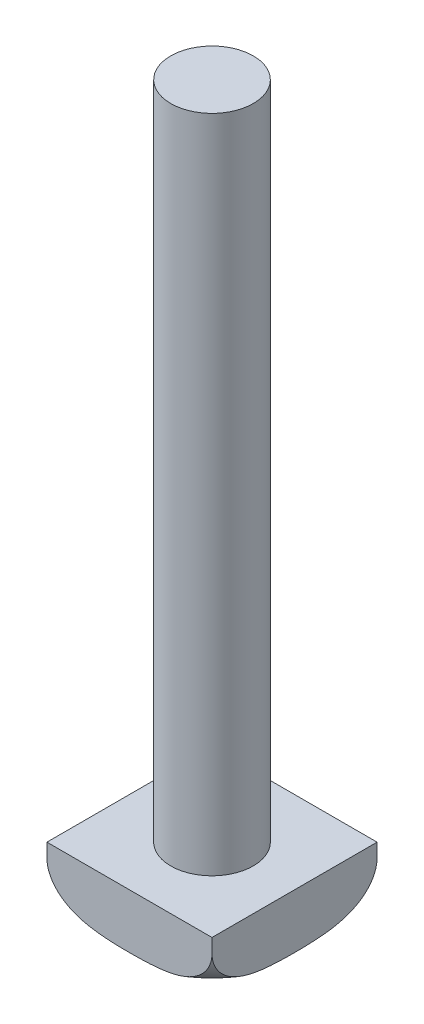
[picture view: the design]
ISO-10303-21;
HEADER;
FILE_DESCRIPTION(('STEP AP214'),'2;1');
FILE_NAME('part.step','',(''),(''),'','','');
FILE_SCHEMA(('AUTOMOTIVE_DESIGN { 1 0 10303 214 1 1 1 1 }'));
ENDSEC;
DATA;
#1=APPLICATION_CONTEXT('core data for automotive mechanical design processes');
#2=APPLICATION_PROTOCOL_DEFINITION('international standard','automotive_design',2000,#1);
#3=PRODUCT_CONTEXT('',#1,'mechanical');
#4=PRODUCT('Part','Part','',(#3));
#5=PRODUCT_RELATED_PRODUCT_CATEGORY('part','',(#4));
#6=PRODUCT_DEFINITION_FORMATION('','',#4);
#7=PRODUCT_DEFINITION_CONTEXT('part definition',#1,'design');
#8=PRODUCT_DEFINITION('design','',#6,#7);
#9=PRODUCT_DEFINITION_SHAPE('','',#8);
#10=(LENGTH_UNIT() NAMED_UNIT(*) SI_UNIT(.MILLI.,.METRE.));
#11=(NAMED_UNIT(*) PLANE_ANGLE_UNIT() SI_UNIT($,.RADIAN.));
#12=(NAMED_UNIT(*) SI_UNIT($,.STERADIAN.) SOLID_ANGLE_UNIT());
#13=UNCERTAINTY_MEASURE_WITH_UNIT(LENGTH_MEASURE(1.E-05),#10,'distance_accuracy_value','');
#14=(GEOMETRIC_REPRESENTATION_CONTEXT(3) GLOBAL_UNCERTAINTY_ASSIGNED_CONTEXT((#13)) GLOBAL_UNIT_ASSIGNED_CONTEXT((#10,
#11,#12)) REPRESENTATION_CONTEXT('',''));
#15=CARTESIAN_POINT('',(0.,0.,0.));
#16=DIRECTION('',(0.,0.,1.));
#17=DIRECTION('',(1.,0.,0.));
#18=AXIS2_PLACEMENT_3D('',#15,#16,#17);
#19=CARTESIAN_POINT('',(-12.,-8.,-12.));
#20=DIRECTION('',(-1.,0.,0.));
#21=DIRECTION('',(0.,0.,1.));
#22=AXIS2_PLACEMENT_3D('',#19,#20,#21);
#23=PLANE('',#22);
#24=DIRECTION('',(0.,1.,0.));
#25=VECTOR('',#24,1.);
#26=CARTESIAN_POINT('',(-12.,-8.,-12.));
#27=LINE('',#26,#25);
#28=CARTESIAN_POINT('',(-12.,-2.,-12.));
#29=VERTEX_POINT('',#28);
#30=CARTESIAN_POINT('',(-12.,0.,-12.));
#31=VERTEX_POINT('',#30);
#32=EDGE_CURVE('E68',#29,#31,#27,.T.);
#33=ORIENTED_EDGE('',*,*,#32,.F.);
#34=CARTESIAN_POINT('',(-12.,-7.9110285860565,0.));
#35=CARTESIAN_POINT('',(-12.,-7.91102969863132,0.219013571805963));
#36=CARTESIAN_POINT('',(-12.,-7.90999326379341,0.438027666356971));
#37=CARTESIAN_POINT('',(-12.,-7.90574714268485,0.876036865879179));
#38=CARTESIAN_POINT('',(-12.,-7.90253743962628,1.09503197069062));
#39=CARTESIAN_POINT('',(-12.,-7.8936366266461,1.53302104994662));
#40=CARTESIAN_POINT('',(-12.,-7.88794497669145,1.75201501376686));
#41=CARTESIAN_POINT('',(-12.,-7.87358073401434,2.18990531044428));
#42=CARTESIAN_POINT('',(-12.,-7.8649081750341,2.40880164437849));
#43=CARTESIAN_POINT('',(-12.,-7.84389210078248,2.84663378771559));
#44=CARTESIAN_POINT('',(-12.,-7.83154505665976,3.06556943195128));
#45=CARTESIAN_POINT('',(-12.,-7.80233781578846,3.50314333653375));
#46=CARTESIAN_POINT('',(-12.,-7.78547766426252,3.72178159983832));
#47=CARTESIAN_POINT('',(-12.,-7.74626053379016,4.15849107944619));
#48=CARTESIAN_POINT('',(-12.,-7.72390564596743,4.37656247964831));
#49=CARTESIAN_POINT('',(-12.,-7.67257977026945,4.81192697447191));
#50=CARTESIAN_POINT('',(-12.,-7.64360896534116,5.0292200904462));
#51=CARTESIAN_POINT('',(-12.,-7.56973816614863,5.51592981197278));
#52=CARTESIAN_POINT('',(-12.,-7.52267302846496,5.78502690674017));
#53=CARTESIAN_POINT('',(-12.,-7.41380940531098,6.32030821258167));
#54=CARTESIAN_POINT('',(-12.,-7.35200886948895,6.58649201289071));
#55=CARTESIAN_POINT('',(-12.,-7.21108699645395,7.11376722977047));
#56=CARTESIAN_POINT('',(-12.,-7.13200012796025,7.37486766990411));
#57=CARTESIAN_POINT('',(-12.,-6.95374614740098,7.89008904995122));
#58=CARTESIAN_POINT('',(-12.,-6.85458163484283,8.14421088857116));
#59=CARTESIAN_POINT('',(-12.,-6.59200086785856,8.73575962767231));
#60=CARTESIAN_POINT('',(-12.,-6.41841714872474,9.0688842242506));
#61=CARTESIAN_POINT('',(-12.,-6.12164363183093,9.54560920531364));
#62=CARTESIAN_POINT('',(-12.,-6.01666076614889,9.70068126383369));
#63=CARTESIAN_POINT('',(-12.,-5.79403053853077,10.0014964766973));
#64=CARTESIAN_POINT('',(-12.,-5.67638648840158,10.1472420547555));
#65=CARTESIAN_POINT('',(-12.,-5.45487933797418,10.3972730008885));
#66=CARTESIAN_POINT('',(-12.,-5.35347698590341,10.5037435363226));
#67=CARTESIAN_POINT('',(-12.,-5.14279674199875,10.7085711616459));
#68=CARTESIAN_POINT('',(-12.,-5.03352073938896,10.8069301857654));
#69=CARTESIAN_POINT('',(-12.,-4.80726648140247,10.9944208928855));
#70=CARTESIAN_POINT('',(-12.,-4.69028689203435,11.0835509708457));
#71=CARTESIAN_POINT('',(-12.,-4.44910125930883,11.2513406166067));
#72=CARTESIAN_POINT('',(-12.,-4.3248985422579,11.330004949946));
#73=CARTESIAN_POINT('',(-12.,-4.06863035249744,11.4764239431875));
#74=CARTESIAN_POINT('',(-12.,-3.93650144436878,11.5440679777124));
#75=CARTESIAN_POINT('',(-12.,-3.6664208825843,11.6663517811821));
#76=CARTESIAN_POINT('',(-12.,-3.52847233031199,11.7209983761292));
#77=CARTESIAN_POINT('',(-12.,-3.24787660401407,11.8162983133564));
#78=CARTESIAN_POINT('',(-12.,-3.10523150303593,11.8569577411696));
#79=CARTESIAN_POINT('',(-12.,-2.81654054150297,11.9234999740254));
#80=CARTESIAN_POINT('',(-12.,-2.67049527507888,11.9493853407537));
#81=CARTESIAN_POINT('',(-12.,-2.39771004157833,11.9832224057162));
#82=CARTESIAN_POINT('',(-12.,-2.27122026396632,11.9932206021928));
#83=CARTESIAN_POINT('',(-12.,-2.01785681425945,12.0018542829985));
#84=CARTESIAN_POINT('',(-12.,-1.89098317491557,12.0004907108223));
#85=CARTESIAN_POINT('',(-12.,-1.63790716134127,11.9864242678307));
#86=CARTESIAN_POINT('',(-12.,-1.51170459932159,11.9737247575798));
#87=CARTESIAN_POINT('',(-12.,-1.26092539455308,11.937191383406));
#88=CARTESIAN_POINT('',(-12.,-1.13634874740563,11.9133575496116));
#89=CARTESIAN_POINT('',(-12.,-0.896493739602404,11.8565133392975));
#90=CARTESIAN_POINT('',(-12.,-0.781079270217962,11.824075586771));
#91=CARTESIAN_POINT('',(-12.,-0.553227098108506,11.7500001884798));
#92=CARTESIAN_POINT('',(-12.,-0.440790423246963,11.7083594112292));
#93=CARTESIAN_POINT('',(-12.,-0.10901494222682,11.5704002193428));
#94=CARTESIAN_POINT('',(-12.,0.105008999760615,11.4609917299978));
#95=CARTESIAN_POINT('',(-12.,0.529245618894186,11.2033409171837));
#96=CARTESIAN_POINT('',(-12.,0.738093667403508,11.052882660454));
#97=CARTESIAN_POINT('',(-12.,1.1323552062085,10.7237991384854));
#98=CARTESIAN_POINT('',(-12.,1.31775055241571,10.5451523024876));
#99=CARTESIAN_POINT('',(-12.,1.62254806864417,10.2114249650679));
#100=CARTESIAN_POINT('',(-12.,1.74710972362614,10.0609788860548));
#101=CARTESIAN_POINT('',(-12.,1.98246993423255,9.74964225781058));
#102=CARTESIAN_POINT('',(-12.,2.09326266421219,9.58874733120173));
#103=CARTESIAN_POINT('',(-12.,2.40581905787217,9.09328545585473));
#104=CARTESIAN_POINT('',(-12.,2.587676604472,8.74603704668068));
#105=CARTESIAN_POINT('',(-12.,2.8739747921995,8.10008122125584));
#106=CARTESIAN_POINT('',(-12.,2.98657270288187,7.80482413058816));
#107=CARTESIAN_POINT('',(-12.,3.18549424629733,7.20541001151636));
#108=CARTESIAN_POINT('',(-12.,3.27179863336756,6.90124664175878));
#109=CARTESIAN_POINT('',(-12.,3.42251739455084,6.2865233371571));
#110=CARTESIAN_POINT('',(-12.,3.4868517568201,5.97594429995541));
#111=CARTESIAN_POINT('',(-12.,3.59736694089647,5.3517420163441));
#112=CARTESIAN_POINT('',(-12.,3.64355298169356,5.03811967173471));
#113=CARTESIAN_POINT('',(-12.,3.72167895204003,4.40870301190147));
#114=CARTESIAN_POINT('',(-12.,3.75359817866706,4.0929062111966));
#115=CARTESIAN_POINT('',(-12.,3.8064824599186,3.46037371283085));
#116=CARTESIAN_POINT('',(-12.,3.82744548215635,3.14363785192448));
#117=CARTESIAN_POINT('',(-12.,3.86122922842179,2.50948037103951));
#118=CARTESIAN_POINT('',(-12.,3.87404293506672,2.19205839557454));
#119=CARTESIAN_POINT('',(-12.,3.8936152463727,1.55706059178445));
#120=CARTESIAN_POINT('',(-12.,3.90037426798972,1.23948477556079));
#121=CARTESIAN_POINT('',(-12.,3.90914967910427,0.604217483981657));
#122=CARTESIAN_POINT('',(-12.,3.91116525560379,0.286525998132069));
#123=CARTESIAN_POINT('',(-12.,3.91087781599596,-0.348865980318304));
#124=CARTESIAN_POINT('',(-12.,3.90857465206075,-0.666566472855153));
#125=CARTESIAN_POINT('',(-12.,3.89916663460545,-1.30170933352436));
#126=CARTESIAN_POINT('',(-12.,3.89206468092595,-1.61915174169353));
#127=CARTESIAN_POINT('',(-12.,3.87169775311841,-2.25382875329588));
#128=CARTESIAN_POINT('',(-12.,3.85843318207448,-2.57106336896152));
#129=CARTESIAN_POINT('',(-12.,3.82272034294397,-3.22079545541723));
#130=CARTESIAN_POINT('',(-12.,3.79984990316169,-3.55327096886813));
#131=CARTESIAN_POINT('',(-12.,3.74162902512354,-4.21723380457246));
#132=CARTESIAN_POINT('',(-12.,3.70627642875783,-4.54872094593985));
#133=CARTESIAN_POINT('',(-12.,3.61917575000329,-5.20892535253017));
#134=CARTESIAN_POINT('',(-12.,3.56746069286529,-5.53764683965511));
#135=CARTESIAN_POINT('',(-12.,3.44311973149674,-6.19111428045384));
#136=CARTESIAN_POINT('',(-12.,3.37050185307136,-6.51586171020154));
#137=CARTESIAN_POINT('',(-12.,3.22557307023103,-7.06051440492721));
#138=CARTESIAN_POINT('',(-12.,3.15992893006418,-7.28217605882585));
#139=CARTESIAN_POINT('',(-12.,3.01453978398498,-7.72081663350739));
#140=CARTESIAN_POINT('',(-12.,2.93479256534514,-7.93779481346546));
#141=CARTESIAN_POINT('',(-12.,2.67195366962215,-8.57887096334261));
#142=CARTESIAN_POINT('',(-12.,2.4650724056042,-8.99388884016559));
#143=CARTESIAN_POINT('',(-12.,2.04688649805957,-9.66573179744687));
#144=CARTESIAN_POINT('',(-12.,1.85384775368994,-9.93380229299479));
#145=CARTESIAN_POINT('',(-12.,1.53460329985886,-10.3104792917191));
#146=CARTESIAN_POINT('',(-12.,1.42326494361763,-10.4317793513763));
#147=CARTESIAN_POINT('',(-12.,1.19066148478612,-10.6644942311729));
#148=CARTESIAN_POINT('',(-12.,1.06939830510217,-10.7759109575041));
#149=CARTESIAN_POINT('',(-12.,0.839451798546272,-10.9686160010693));
#150=CARTESIAN_POINT('',(-12.,0.73231572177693,-11.0517541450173));
#151=CARTESIAN_POINT('',(-12.,0.511809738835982,-11.2092927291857));
#152=CARTESIAN_POINT('',(-12.,0.398441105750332,-11.2836949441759));
#153=CARTESIAN_POINT('',(-12.,0.165895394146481,-11.4228563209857));
#154=CARTESIAN_POINT('',(-12.,0.0467174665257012,-11.4876140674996));
#155=CARTESIAN_POINT('',(-12.,-0.196754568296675,-11.6065554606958));
#156=CARTESIAN_POINT('',(-12.,-0.321046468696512,-11.6607436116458));
#157=CARTESIAN_POINT('',(-12.,-0.574834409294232,-11.7580847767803));
#158=CARTESIAN_POINT('',(-12.,-0.704359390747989,-11.801162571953));
#159=CARTESIAN_POINT('',(-12.,-0.966798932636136,-11.8750880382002));
#160=CARTESIAN_POINT('',(-12.,-1.09971189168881,-11.9059413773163));
#161=CARTESIAN_POINT('',(-12.,-1.36785149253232,-11.9549089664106));
#162=CARTESIAN_POINT('',(-12.,-1.50307782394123,-11.9730249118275));
#163=CARTESIAN_POINT('',(-12.,-1.77463986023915,-11.9961963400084));
#164=CARTESIAN_POINT('',(-12.,-1.91097545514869,-12.0012531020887));
#165=CARTESIAN_POINT('',(-12.,-2.16915561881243,-11.9983805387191));
#166=CARTESIAN_POINT('',(-12.,-2.29101669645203,-11.9917606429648));
#167=CARTESIAN_POINT('',(-12.,-2.53376216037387,-11.9680903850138));
#168=CARTESIAN_POINT('',(-12.,-2.65464622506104,-11.9510367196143));
#169=CARTESIAN_POINT('',(-12.,-2.89446289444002,-11.9067519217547));
#170=CARTESIAN_POINT('',(-12.,-3.01339651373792,-11.8795262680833));
#171=CARTESIAN_POINT('',(-12.,-3.24862414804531,-11.8152635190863));
#172=CARTESIAN_POINT('',(-12.,-3.36491714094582,-11.7782226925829));
#173=CARTESIAN_POINT('',(-12.,-3.59350120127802,-11.6950405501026));
#174=CARTESIAN_POINT('',(-12.,-3.70581019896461,-11.648948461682));
#175=CARTESIAN_POINT('',(-12.,-3.926488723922,-11.548108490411));
#176=CARTESIAN_POINT('',(-12.,-4.03485685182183,-11.4933575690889));
#177=CARTESIAN_POINT('',(-12.,-4.35322873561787,-11.3170486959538));
#178=CARTESIAN_POINT('',(-12.,-4.55664292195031,-11.1833816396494));
#179=CARTESIAN_POINT('',(-12.,-4.96409580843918,-10.8730496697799));
#180=CARTESIAN_POINT('',(-12.,-5.16573208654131,-10.6932693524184));
#181=CARTESIAN_POINT('',(-12.,-5.54232978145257,-10.3077301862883));
#182=CARTESIAN_POINT('',(-12.,-5.71727899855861,-10.1019595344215));
#183=CARTESIAN_POINT('',(-12.,-6.01035552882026,-9.71139282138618));
#184=CARTESIAN_POINT('',(-12.,-6.13298316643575,-9.52991865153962));
#185=CARTESIAN_POINT('',(-12.,-6.36172605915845,-9.15676042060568));
#186=CARTESIAN_POINT('',(-12.,-6.46783253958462,-8.96507100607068));
#187=CARTESIAN_POINT('',(-12.,-6.66475191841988,-8.57354683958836));
#188=CARTESIAN_POINT('',(-12.,-6.75553226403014,-8.37369584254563));
#189=CARTESIAN_POINT('',(-12.,-6.92281860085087,-7.96820435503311));
#190=CARTESIAN_POINT('',(-12.,-6.99932627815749,-7.76256455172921));
#191=CARTESIAN_POINT('',(-12.,-7.22643844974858,-7.08929142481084));
#192=CARTESIAN_POINT('',(-12.,-7.35132807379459,-6.61288508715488));
#193=CARTESIAN_POINT('',(-12.,-7.5022671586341,-5.89102752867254));
#194=CARTESIAN_POINT('',(-12.,-7.54654262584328,-5.64893254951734));
#195=CARTESIAN_POINT('',(-12.,-7.6248221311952,-5.16305335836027));
#196=CARTESIAN_POINT('',(-12.,-7.65882656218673,-4.91926921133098));
#197=CARTESIAN_POINT('',(-12.,-7.71841574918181,-4.42984301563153));
#198=CARTESIAN_POINT('',(-12.,-7.74397047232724,-4.18419744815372));
#199=CARTESIAN_POINT('',(-12.,-7.78810771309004,-3.69228759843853));
#200=CARTESIAN_POINT('',(-12.,-7.80669015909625,-3.44602330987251));
#201=CARTESIAN_POINT('',(-12.,-7.83827221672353,-2.95332835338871));
#202=CARTESIAN_POINT('',(-12.,-7.85127588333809,-2.7068979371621));
#203=CARTESIAN_POINT('',(-12.,-7.87288468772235,-2.21385458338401));
#204=CARTESIAN_POINT('',(-12.,-7.88148991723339,-1.96724164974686));
#205=CARTESIAN_POINT('',(-12.,-7.89232149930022,-1.57711739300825));
#206=CARTESIAN_POINT('',(-12.,-7.89571038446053,-1.43363634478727));
#207=CARTESIAN_POINT('',(-12.,-7.90142448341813,-1.14665252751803));
#208=CARTESIAN_POINT('',(-12.,-7.90374969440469,-1.00314975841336));
#209=CARTESIAN_POINT('',(-12.,-7.90742828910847,-0.716374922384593));
#210=CARTESIAN_POINT('',(-12.,-7.90878331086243,-0.573102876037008));
#211=CARTESIAN_POINT('',(-12.,-7.9105830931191,-0.286553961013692));
#212=CARTESIAN_POINT('',(-12.,-7.91102785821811,-0.143277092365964));
#213=CARTESIAN_POINT('',(-12.,-7.9110285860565,0.));
#214=B_SPLINE_CURVE_WITH_KNOTS('',3,(#34,#35,#36,#37,#38,#39,#40,#41,#42,#43,#44,#45,#46,#47,
#48,#49,#50,#51,#52,#53,#54,#55,#56,#57,#58,#59,#60,#61,#62,#63,#64,#65,#66,#67,#68,#69,#70,#71,
#72,#73,#74,#75,#76,#77,#78,#79,#80,#81,#82,#83,#84,#85,#86,#87,#88,#89,#90,#91,#92,#93,#94,#95,
#96,#97,#98,#99,#100,#101,#102,#103,#104,#105,#106,#107,#108,#109,#110,#111,#112,#113,#114,#115,
#116,#117,#118,#119,#120,#121,#122,#123,#124,#125,#126,#127,#128,#129,#130,#131,#132,#133,#134,
#135,#136,#137,#138,#139,#140,#141,#142,#143,#144,#145,#146,#147,#148,#149,#150,#151,#152,#153,
#154,#155,#156,#157,#158,#159,#160,#161,#162,#163,#164,#165,#166,#167,#168,#169,#170,#171,#172,
#173,#174,#175,#176,#177,#178,#179,#180,#181,#182,#183,#184,#185,#186,#187,#188,#189,#190,#191,
#192,#193,#194,#195,#196,#197,#198,#199,#200,#201,#202,#203,#204,#205,#206,#207,#208,#209,#210,
#211,#212,#213),.UNSPECIFIED.,.T.,.F.,(4,2,2,2,2,2,2,2,2,2,2,2,2,2,2,2,2,2,2,2,2,2,2,2,2,2,2,2,
2,2,2,2,2,2,2,2,2,2,2,2,2,2,2,2,2,2,2,2,2,2,2,2,2,2,2,2,2,2,2,2,2,2,2,2,2,2,2,2,2,2,2,2,2,2,2,2,
2,2,2,2,2,2,2,2,2,2,2,2,2,4),(0.,0.657039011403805,1.3140830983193,1.971270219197,
2.62844990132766,3.28626276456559,3.94406903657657,4.60162535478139,5.25916349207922,
6.07836208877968,6.8976747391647,7.71536835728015,8.53295617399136,9.65565324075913,
10.2169292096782,10.7780587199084,11.2187658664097,11.6593676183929,12.1000458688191,
12.5405227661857,12.9851800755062,13.4296033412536,13.8738330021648,14.3179856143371,
14.6981459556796,15.0782747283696,15.4582908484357,15.8383059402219,16.1975550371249,
16.5569265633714,17.274999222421,18.0443719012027,18.8143362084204,19.399505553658,
19.9849216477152,21.1561315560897,22.1028947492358,23.0503492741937,24.0012183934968,
24.9518138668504,25.9037843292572,26.8559313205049,27.8088971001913,28.7617972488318,
29.7148607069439,30.6679567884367,31.6204774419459,32.5729358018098,33.5725505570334,
34.572338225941,35.5701207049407,36.5675205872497,37.2605975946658,37.9537834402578,
39.3377688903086,40.3250476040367,40.8184978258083,41.3118526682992,41.7182942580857,
42.124653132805,42.5310715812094,42.9373164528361,43.3462434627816,43.7549806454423,
44.1636634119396,44.5723061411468,44.937985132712,45.303779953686,45.6693780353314,
46.0351152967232,46.3989159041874,46.7628444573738,47.4902491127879,48.297829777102,
49.1057785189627,49.7619424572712,50.418453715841,51.0763423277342,51.7341531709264,
53.2074032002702,53.9456389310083,54.6838464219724,55.4246502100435,56.1654616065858,
56.9057336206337,57.6459901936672,58.0765500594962,58.5071110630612,58.9369433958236,
59.3667735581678),.UNSPECIFIED.);
#215=CARTESIAN_POINT('',(-12.,-2.,12.));
#216=VERTEX_POINT('',#215);
#217=EDGE_CURVE('E89',#29,#216,#214,.T.);
#218=ORIENTED_EDGE('',*,*,#217,.T.);
#219=DIRECTION('',(0.,1.,0.));
#220=VECTOR('',#219,1.);
#221=CARTESIAN_POINT('',(-12.,-8.,12.));
#222=LINE('',#221,#220);
#223=CARTESIAN_POINT('',(-12.,0.,12.));
#224=VERTEX_POINT('',#223);
#225=EDGE_CURVE('E106',#216,#224,#222,.T.);
#226=ORIENTED_EDGE('',*,*,#225,.T.);
#227=DIRECTION('',(0.,0.,1.));
#228=VECTOR('',#227,1.);
#229=CARTESIAN_POINT('',(-12.,0.,-12.));
#230=LINE('',#229,#228);
#231=EDGE_CURVE('E145',#31,#224,#230,.T.);
#232=ORIENTED_EDGE('',*,*,#231,.F.);
#233=EDGE_LOOP('',(#33,#218,#226,#232));
#234=FACE_BOUND('',#233,.T.);
#235=ADVANCED_FACE('F44',(#234),#23,.T.);
#236=CARTESIAN_POINT('',(-12.,-8.,-12.));
#237=DIRECTION('',(0.,0.,-1.));
#238=DIRECTION('',(-1.,0.,0.));
#239=AXIS2_PLACEMENT_3D('',#236,#237,#238);
#240=PLANE('',#239);
#241=DIRECTION('',(0.,1.,0.));
#242=VECTOR('',#241,1.);
#243=CARTESIAN_POINT('',(12.,-8.,-12.));
#244=LINE('',#243,#242);
#245=CARTESIAN_POINT('',(12.,-2.,-12.));
#246=VERTEX_POINT('',#245);
#247=CARTESIAN_POINT('',(12.,0.,-12.));
#248=VERTEX_POINT('',#247);
#249=EDGE_CURVE('E96',#246,#248,#244,.T.);
#250=ORIENTED_EDGE('',*,*,#249,.F.);
#251=CARTESIAN_POINT('',(0.,-7.9110285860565,-12.));
#252=CARTESIAN_POINT('',(-0.219013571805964,-7.91102969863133,-12.));
#253=CARTESIAN_POINT('',(-0.438027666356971,-7.90999326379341,-12.));
#254=CARTESIAN_POINT('',(-0.87603686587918,-7.90574714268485,-12.));
#255=CARTESIAN_POINT('',(-1.09503197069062,-7.90253743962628,-12.));
#256=CARTESIAN_POINT('',(-1.53302104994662,-7.8936366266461,-12.));
#257=CARTESIAN_POINT('',(-1.75201501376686,-7.88794497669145,-12.));
#258=CARTESIAN_POINT('',(-2.18990531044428,-7.87358073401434,-12.));
#259=CARTESIAN_POINT('',(-2.40880164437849,-7.8649081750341,-12.));
#260=CARTESIAN_POINT('',(-2.8466337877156,-7.84389210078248,-12.));
#261=CARTESIAN_POINT('',(-3.06556943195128,-7.83154505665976,-12.));
#262=CARTESIAN_POINT('',(-3.50314333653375,-7.80233781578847,-12.));
#263=CARTESIAN_POINT('',(-3.72178159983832,-7.78547766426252,-12.));
#264=CARTESIAN_POINT('',(-4.15849107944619,-7.74626053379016,-12.));
#265=CARTESIAN_POINT('',(-4.37656247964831,-7.72390564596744,-12.));
#266=CARTESIAN_POINT('',(-4.81192697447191,-7.67257977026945,-12.));
#267=CARTESIAN_POINT('',(-5.0292200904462,-7.64360896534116,-12.));
#268=CARTESIAN_POINT('',(-5.51592981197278,-7.56973816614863,-12.));
#269=CARTESIAN_POINT('',(-5.78502690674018,-7.52267302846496,-12.));
#270=CARTESIAN_POINT('',(-6.32030821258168,-7.41380940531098,-12.));
#271=CARTESIAN_POINT('',(-6.58649201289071,-7.35200886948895,-12.));
#272=CARTESIAN_POINT('',(-7.11376722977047,-7.21108699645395,-12.));
#273=CARTESIAN_POINT('',(-7.37486766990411,-7.13200012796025,-12.));
#274=CARTESIAN_POINT('',(-7.89008904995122,-6.95374614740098,-12.));
#275=CARTESIAN_POINT('',(-8.14421088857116,-6.85458163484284,-12.));
#276=CARTESIAN_POINT('',(-8.73575962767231,-6.59200086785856,-12.));
#277=CARTESIAN_POINT('',(-9.0688842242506,-6.41841714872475,-12.));
#278=CARTESIAN_POINT('',(-9.54560920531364,-6.12164363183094,-12.));
#279=CARTESIAN_POINT('',(-9.70068126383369,-6.0166607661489,-12.));
#280=CARTESIAN_POINT('',(-10.0014964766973,-5.79403053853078,-12.));
#281=CARTESIAN_POINT('',(-10.1472420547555,-5.67638648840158,-12.));
#282=CARTESIAN_POINT('',(-10.3972730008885,-5.45487933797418,-12.));
#283=CARTESIAN_POINT('',(-10.5037435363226,-5.35347698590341,-12.));
#284=CARTESIAN_POINT('',(-10.7085711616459,-5.14279674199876,-12.));
#285=CARTESIAN_POINT('',(-10.8069301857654,-5.03352073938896,-12.));
#286=CARTESIAN_POINT('',(-10.9944208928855,-4.80726648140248,-12.));
#287=CARTESIAN_POINT('',(-11.0835509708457,-4.69028689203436,-12.));
#288=CARTESIAN_POINT('',(-11.2513406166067,-4.44910125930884,-12.));
#289=CARTESIAN_POINT('',(-11.330004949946,-4.32489854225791,-12.));
#290=CARTESIAN_POINT('',(-11.4764239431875,-4.06863035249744,-12.));
#291=CARTESIAN_POINT('',(-11.5440679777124,-3.93650144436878,-12.));
#292=CARTESIAN_POINT('',(-11.6663517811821,-3.66642088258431,-12.));
#293=CARTESIAN_POINT('',(-11.7209983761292,-3.528472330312,-12.));
#294=CARTESIAN_POINT('',(-11.8162983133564,-3.24787660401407,-12.));
#295=CARTESIAN_POINT('',(-11.8569577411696,-3.10523150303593,-12.));
#296=CARTESIAN_POINT('',(-11.9234999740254,-2.81654054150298,-12.));
#297=CARTESIAN_POINT('',(-11.9493853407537,-2.67049527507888,-12.));
#298=CARTESIAN_POINT('',(-11.9832224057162,-2.39771004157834,-12.));
#299=CARTESIAN_POINT('',(-11.9932206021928,-2.27122026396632,-12.));
#300=CARTESIAN_POINT('',(-12.0018542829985,-2.01785681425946,-12.));
#301=CARTESIAN_POINT('',(-12.0004907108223,-1.89098317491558,-12.));
#302=CARTESIAN_POINT('',(-11.9864242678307,-1.63790716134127,-12.));
#303=CARTESIAN_POINT('',(-11.9737247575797,-1.5117045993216,-12.));
#304=CARTESIAN_POINT('',(-11.937191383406,-1.26092539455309,-12.));
#305=CARTESIAN_POINT('',(-11.9133575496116,-1.13634874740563,-12.));
#306=CARTESIAN_POINT('',(-11.8565133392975,-0.896493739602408,-12.));
#307=CARTESIAN_POINT('',(-11.824075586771,-0.781079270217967,-12.));
#308=CARTESIAN_POINT('',(-11.7500001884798,-0.553227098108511,-12.));
#309=CARTESIAN_POINT('',(-11.7083594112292,-0.440790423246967,-12.));
#310=CARTESIAN_POINT('',(-11.5704002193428,-0.109014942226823,-12.));
#311=CARTESIAN_POINT('',(-11.4609917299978,0.10500899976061,-12.));
#312=CARTESIAN_POINT('',(-11.2033409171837,0.52924561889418,-12.));
#313=CARTESIAN_POINT('',(-11.052882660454,0.7380936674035,-12.));
#314=CARTESIAN_POINT('',(-10.7237991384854,1.13235520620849,-12.));
#315=CARTESIAN_POINT('',(-10.5451523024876,1.31775055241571,-12.));
#316=CARTESIAN_POINT('',(-10.2114249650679,1.62254806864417,-12.));
#317=CARTESIAN_POINT('',(-10.0609788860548,1.74710972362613,-12.));
#318=CARTESIAN_POINT('',(-9.74964225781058,1.98246993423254,-12.));
#319=CARTESIAN_POINT('',(-9.58874733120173,2.09326266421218,-12.));
#320=CARTESIAN_POINT('',(-9.09328545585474,2.40581905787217,-12.));
#321=CARTESIAN_POINT('',(-8.74603704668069,2.587676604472,-12.));
#322=CARTESIAN_POINT('',(-8.10008122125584,2.87397479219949,-12.));
#323=CARTESIAN_POINT('',(-7.80482413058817,2.98657270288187,-12.));
#324=CARTESIAN_POINT('',(-7.20541001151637,3.18549424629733,-12.));
#325=CARTESIAN_POINT('',(-6.90124664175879,3.27179863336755,-12.));
#326=CARTESIAN_POINT('',(-6.2865233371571,3.42251739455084,-12.));
#327=CARTESIAN_POINT('',(-5.97594429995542,3.4868517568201,-12.));
#328=CARTESIAN_POINT('',(-5.35174201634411,3.59736694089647,-12.));
#329=CARTESIAN_POINT('',(-5.03811967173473,3.64355298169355,-12.));
#330=CARTESIAN_POINT('',(-4.40870301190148,3.72167895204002,-12.));
#331=CARTESIAN_POINT('',(-4.09290621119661,3.75359817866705,-12.));
#332=CARTESIAN_POINT('',(-3.46037371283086,3.80648245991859,-12.));
#333=CARTESIAN_POINT('',(-3.14363785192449,3.82744548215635,-12.));
#334=CARTESIAN_POINT('',(-2.50948037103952,3.86122922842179,-12.));
#335=CARTESIAN_POINT('',(-2.19205839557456,3.87404293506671,-12.));
#336=CARTESIAN_POINT('',(-1.55706059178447,3.8936152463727,-12.));
#337=CARTESIAN_POINT('',(-1.2394847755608,3.90037426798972,-12.));
#338=CARTESIAN_POINT('',(-0.604217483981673,3.90914967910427,-12.));
#339=CARTESIAN_POINT('',(-0.286525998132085,3.91116525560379,-12.));
#340=CARTESIAN_POINT('',(0.348865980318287,3.91087781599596,-12.));
#341=CARTESIAN_POINT('',(0.666566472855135,3.90857465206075,-12.));
#342=CARTESIAN_POINT('',(1.30170933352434,3.89916663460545,-12.));
#343=CARTESIAN_POINT('',(1.61915174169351,3.89206468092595,-12.));
#344=CARTESIAN_POINT('',(2.25382875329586,3.87169775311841,-12.));
#345=CARTESIAN_POINT('',(2.5710633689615,3.85843318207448,-12.));
#346=CARTESIAN_POINT('',(3.22079545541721,3.82272034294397,-12.));
#347=CARTESIAN_POINT('',(3.55327096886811,3.7998499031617,-12.));
#348=CARTESIAN_POINT('',(4.21723380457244,3.74162902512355,-12.));
#349=CARTESIAN_POINT('',(4.54872094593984,3.70627642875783,-12.));
#350=CARTESIAN_POINT('',(5.20892535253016,3.61917575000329,-12.));
#351=CARTESIAN_POINT('',(5.53764683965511,3.56746069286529,-12.));
#352=CARTESIAN_POINT('',(6.19111428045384,3.44311973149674,-12.));
#353=CARTESIAN_POINT('',(6.51586171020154,3.37050185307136,-12.));
#354=CARTESIAN_POINT('',(7.06051440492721,3.22557307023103,-12.));
#355=CARTESIAN_POINT('',(7.28217605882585,3.15992893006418,-12.));
#356=CARTESIAN_POINT('',(7.7208166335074,3.01453978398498,-12.));
#357=CARTESIAN_POINT('',(7.93779481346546,2.93479256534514,-12.));
#358=CARTESIAN_POINT('',(8.57887096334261,2.67195366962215,-12.));
#359=CARTESIAN_POINT('',(8.99388884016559,2.46507240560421,-12.));
#360=CARTESIAN_POINT('',(9.66573179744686,2.04688649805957,-12.));
#361=CARTESIAN_POINT('',(9.93380229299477,1.85384775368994,-12.));
#362=CARTESIAN_POINT('',(10.3104792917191,1.53460329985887,-12.));
#363=CARTESIAN_POINT('',(10.4317793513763,1.42326494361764,-12.));
#364=CARTESIAN_POINT('',(10.6644942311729,1.19066148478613,-12.));
#365=CARTESIAN_POINT('',(10.7759109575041,1.06939830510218,-12.));
#366=CARTESIAN_POINT('',(10.9686160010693,0.839451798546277,-12.));
#367=CARTESIAN_POINT('',(11.0517541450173,0.732315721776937,-12.));
#368=CARTESIAN_POINT('',(11.2092927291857,0.511809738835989,-12.));
#369=CARTESIAN_POINT('',(11.2836949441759,0.398441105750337,-12.));
#370=CARTESIAN_POINT('',(11.4228563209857,0.165895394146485,-12.));
#371=CARTESIAN_POINT('',(11.4876140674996,0.0467174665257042,-12.));
#372=CARTESIAN_POINT('',(11.6065554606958,-0.196754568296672,-12.));
#373=CARTESIAN_POINT('',(11.6607436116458,-0.321046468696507,-12.));
#374=CARTESIAN_POINT('',(11.7580847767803,-0.574834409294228,-12.));
#375=CARTESIAN_POINT('',(11.801162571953,-0.704359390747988,-12.));
#376=CARTESIAN_POINT('',(11.8750880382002,-0.966798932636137,-12.));
#377=CARTESIAN_POINT('',(11.9059413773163,-1.09971189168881,-12.));
#378=CARTESIAN_POINT('',(11.9549089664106,-1.36785149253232,-12.));
#379=CARTESIAN_POINT('',(11.9730249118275,-1.50307782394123,-12.));
#380=CARTESIAN_POINT('',(11.9961963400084,-1.77463986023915,-12.));
#381=CARTESIAN_POINT('',(12.0012531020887,-1.91097545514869,-12.));
#382=CARTESIAN_POINT('',(11.9983805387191,-2.16915561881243,-12.));
#383=CARTESIAN_POINT('',(11.9917606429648,-2.29101669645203,-12.));
#384=CARTESIAN_POINT('',(11.9680903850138,-2.53376216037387,-12.));
#385=CARTESIAN_POINT('',(11.9510367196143,-2.65464622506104,-12.));
#386=CARTESIAN_POINT('',(11.9067519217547,-2.89446289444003,-12.));
#387=CARTESIAN_POINT('',(11.8795262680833,-3.01339651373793,-12.));
#388=CARTESIAN_POINT('',(11.8152635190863,-3.24862414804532,-12.));
#389=CARTESIAN_POINT('',(11.7782226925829,-3.36491714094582,-12.));
#390=CARTESIAN_POINT('',(11.6950405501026,-3.59350120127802,-12.));
#391=CARTESIAN_POINT('',(11.648948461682,-3.70581019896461,-12.));
#392=CARTESIAN_POINT('',(11.548108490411,-3.926488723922,-12.));
#393=CARTESIAN_POINT('',(11.4933575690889,-4.03485685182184,-12.));
#394=CARTESIAN_POINT('',(11.3170486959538,-4.35322873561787,-12.));
#395=CARTESIAN_POINT('',(11.1833816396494,-4.55664292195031,-12.));
#396=CARTESIAN_POINT('',(10.8730496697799,-4.96409580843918,-12.));
#397=CARTESIAN_POINT('',(10.6932693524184,-5.1657320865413,-12.));
#398=CARTESIAN_POINT('',(10.3077301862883,-5.54232978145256,-12.));
#399=CARTESIAN_POINT('',(10.1019595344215,-5.7172789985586,-12.));
#400=CARTESIAN_POINT('',(9.71139282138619,-6.01035552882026,-12.));
#401=CARTESIAN_POINT('',(9.52991865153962,-6.13298316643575,-12.));
#402=CARTESIAN_POINT('',(9.15676042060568,-6.36172605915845,-12.));
#403=CARTESIAN_POINT('',(8.96507100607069,-6.46783253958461,-12.));
#404=CARTESIAN_POINT('',(8.57354683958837,-6.66475191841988,-12.));
#405=CARTESIAN_POINT('',(8.37369584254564,-6.75553226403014,-12.));
#406=CARTESIAN_POINT('',(7.96820435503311,-6.92281860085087,-12.));
#407=CARTESIAN_POINT('',(7.76256455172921,-6.99932627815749,-12.));
#408=CARTESIAN_POINT('',(7.08929142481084,-7.22643844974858,-12.));
#409=CARTESIAN_POINT('',(6.61288508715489,-7.35132807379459,-12.));
#410=CARTESIAN_POINT('',(5.89102752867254,-7.5022671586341,-12.));
#411=CARTESIAN_POINT('',(5.64893254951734,-7.54654262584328,-12.));
#412=CARTESIAN_POINT('',(5.16305335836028,-7.6248221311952,-12.));
#413=CARTESIAN_POINT('',(4.91926921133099,-7.65882656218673,-12.));
#414=CARTESIAN_POINT('',(4.42984301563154,-7.71841574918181,-12.));
#415=CARTESIAN_POINT('',(4.18419744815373,-7.74397047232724,-12.));
#416=CARTESIAN_POINT('',(3.69228759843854,-7.78810771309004,-12.));
#417=CARTESIAN_POINT('',(3.44602330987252,-7.80669015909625,-12.));
#418=CARTESIAN_POINT('',(2.95332835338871,-7.83827221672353,-12.));
#419=CARTESIAN_POINT('',(2.70689793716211,-7.8512758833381,-12.));
#420=CARTESIAN_POINT('',(2.21385458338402,-7.87288468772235,-12.));
#421=CARTESIAN_POINT('',(1.96724164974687,-7.88148991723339,-12.));
#422=CARTESIAN_POINT('',(1.57711739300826,-7.89232149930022,-12.));
#423=CARTESIAN_POINT('',(1.43363634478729,-7.89571038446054,-12.));
#424=CARTESIAN_POINT('',(1.14665252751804,-7.90142448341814,-12.));
#425=CARTESIAN_POINT('',(1.00314975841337,-7.90374969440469,-12.));
#426=CARTESIAN_POINT('',(0.7163749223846,-7.90742828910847,-12.));
#427=CARTESIAN_POINT('',(0.573102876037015,-7.90878331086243,-12.));
#428=CARTESIAN_POINT('',(0.286553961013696,-7.91058309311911,-12.));
#429=CARTESIAN_POINT('',(0.143277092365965,-7.91102785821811,-12.));
#430=CARTESIAN_POINT('',(0.,-7.9110285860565,-12.));
#431=B_SPLINE_CURVE_WITH_KNOTS('',3,(#251,#252,#253,#254,#255,#256,#257,#258,#259,#260,#261,
#262,#263,#264,#265,#266,#267,#268,#269,#270,#271,#272,#273,#274,#275,#276,#277,#278,#279,#280,
#281,#282,#283,#284,#285,#286,#287,#288,#289,#290,#291,#292,#293,#294,#295,#296,#297,#298,#299,
#300,#301,#302,#303,#304,#305,#306,#307,#308,#309,#310,#311,#312,#313,#314,#315,#316,#317,#318,
#319,#320,#321,#322,#323,#324,#325,#326,#327,#328,#329,#330,#331,#332,#333,#334,#335,#336,#337,
#338,#339,#340,#341,#342,#343,#344,#345,#346,#347,#348,#349,#350,#351,#352,#353,#354,#355,#356,
#357,#358,#359,#360,#361,#362,#363,#364,#365,#366,#367,#368,#369,#370,#371,#372,#373,#374,#375,
#376,#377,#378,#379,#380,#381,#382,#383,#384,#385,#386,#387,#388,#389,#390,#391,#392,#393,#394,
#395,#396,#397,#398,#399,#400,#401,#402,#403,#404,#405,#406,#407,#408,#409,#410,#411,#412,#413,
#414,#415,#416,#417,#418,#419,#420,#421,#422,#423,#424,#425,#426,#427,#428,#429,#430),
.UNSPECIFIED.,.T.,.F.,(4,2,2,2,2,2,2,2,2,2,2,2,2,2,2,2,2,2,2,2,2,2,2,2,2,2,2,2,2,2,2,2,2,2,2,2,
2,2,2,2,2,2,2,2,2,2,2,2,2,2,2,2,2,2,2,2,2,2,2,2,2,2,2,2,2,2,2,2,2,2,2,2,2,2,2,2,2,2,2,2,2,2,2,2,
2,2,2,2,2,4),(0.,0.657039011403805,1.3140830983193,1.971270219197,2.62844990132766,
3.28626276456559,3.94406903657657,4.60162535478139,5.25916349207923,6.07836208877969,
6.8976747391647,7.71536835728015,8.53295617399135,9.65565324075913,10.2169292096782,
10.7780587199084,11.2187658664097,11.6593676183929,12.1000458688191,12.5405227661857,
12.9851800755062,13.4296033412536,13.8738330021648,14.3179856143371,14.6981459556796,
15.0782747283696,15.4582908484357,15.8383059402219,16.1975550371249,16.5569265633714,
17.274999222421,18.0443719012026,18.8143362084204,19.399505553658,19.9849216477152,
21.1561315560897,22.1028947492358,23.0503492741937,24.0012183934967,24.9518138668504,
25.9037843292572,26.8559313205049,27.8088971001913,28.7617972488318,29.7148607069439,
30.6679567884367,31.6204774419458,32.5729358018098,33.5725505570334,34.572338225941,
35.5701207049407,36.5675205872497,37.2605975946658,37.9537834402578,39.3377688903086,
40.3250476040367,40.8184978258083,41.3118526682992,41.7182942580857,42.124653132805,
42.5310715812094,42.9373164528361,43.3462434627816,43.7549806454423,44.1636634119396,
44.5723061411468,44.937985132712,45.303779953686,45.6693780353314,46.0351152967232,
46.3989159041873,46.7628444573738,47.4902491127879,48.297829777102,49.1057785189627,
49.7619424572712,50.418453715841,51.0763423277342,51.7341531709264,53.2074032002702,
53.9456389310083,54.6838464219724,55.4246502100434,56.1654616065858,56.9057336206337,
57.6459901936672,58.0765500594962,58.5071110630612,58.9369433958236,59.3667735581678),.UNSPECIFIED.);
#432=EDGE_CURVE('E85',#246,#29,#431,.T.);
#433=ORIENTED_EDGE('',*,*,#432,.T.);
#434=ORIENTED_EDGE('',*,*,#32,.T.);
#435=DIRECTION('',(-1.,0.,0.));
#436=VECTOR('',#435,1.);
#437=CARTESIAN_POINT('',(-12.,0.,-12.));
#438=LINE('',#437,#436);
#439=EDGE_CURVE('E103',#248,#31,#438,.T.);
#440=ORIENTED_EDGE('',*,*,#439,.F.);
#441=EDGE_LOOP('',(#250,#433,#434,#440));
#442=FACE_BOUND('',#441,.T.);
#443=ADVANCED_FACE('F101',(#442),#240,.T.);
#444=CARTESIAN_POINT('',(12.,-8.,-12.));
#445=DIRECTION('',(1.,0.,0.));
#446=DIRECTION('',(0.,0.,-1.));
#447=AXIS2_PLACEMENT_3D('',#444,#445,#446);
#448=PLANE('',#447);
#449=DIRECTION('',(0.,1.,0.));
#450=VECTOR('',#449,1.);
#451=CARTESIAN_POINT('',(12.,-8.,12.));
#452=LINE('',#451,#450);
#453=CARTESIAN_POINT('',(12.,-2.,12.));
#454=VERTEX_POINT('',#453);
#455=CARTESIAN_POINT('',(12.,0.,12.));
#456=VERTEX_POINT('',#455);
#457=EDGE_CURVE('E98',#454,#456,#452,.T.);
#458=ORIENTED_EDGE('',*,*,#457,.F.);
#459=CARTESIAN_POINT('',(12.,-7.9110285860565,0.));
#460=CARTESIAN_POINT('',(12.,-7.91102969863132,-0.21901357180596));
#461=CARTESIAN_POINT('',(12.,-7.90999326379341,-0.438027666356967));
#462=CARTESIAN_POINT('',(12.,-7.90574714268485,-0.876036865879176));
#463=CARTESIAN_POINT('',(12.,-7.90253743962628,-1.09503197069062));
#464=CARTESIAN_POINT('',(12.,-7.8936366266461,-1.53302104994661));
#465=CARTESIAN_POINT('',(12.,-7.88794497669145,-1.75201501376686));
#466=CARTESIAN_POINT('',(12.,-7.87358073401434,-2.18990531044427));
#467=CARTESIAN_POINT('',(12.,-7.8649081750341,-2.40880164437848));
#468=CARTESIAN_POINT('',(12.,-7.84389210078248,-2.84663378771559));
#469=CARTESIAN_POINT('',(12.,-7.83154505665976,-3.06556943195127));
#470=CARTESIAN_POINT('',(12.,-7.80233781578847,-3.50314333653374));
#471=CARTESIAN_POINT('',(12.,-7.78547766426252,-3.72178159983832));
#472=CARTESIAN_POINT('',(12.,-7.74626053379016,-4.15849107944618));
#473=CARTESIAN_POINT('',(12.,-7.72390564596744,-4.37656247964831));
#474=CARTESIAN_POINT('',(12.,-7.67257977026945,-4.8119269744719));
#475=CARTESIAN_POINT('',(12.,-7.64360896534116,-5.0292200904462));
#476=CARTESIAN_POINT('',(12.,-7.56973816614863,-5.51592981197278));
#477=CARTESIAN_POINT('',(12.,-7.52267302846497,-5.78502690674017));
#478=CARTESIAN_POINT('',(12.,-7.41380940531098,-6.32030821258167));
#479=CARTESIAN_POINT('',(12.,-7.35200886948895,-6.58649201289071));
#480=CARTESIAN_POINT('',(12.,-7.21108699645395,-7.11376722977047));
#481=CARTESIAN_POINT('',(12.,-7.13200012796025,-7.37486766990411));
#482=CARTESIAN_POINT('',(12.,-6.95374614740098,-7.89008904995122));
#483=CARTESIAN_POINT('',(12.,-6.85458163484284,-8.14421088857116));
#484=CARTESIAN_POINT('',(12.,-6.59200086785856,-8.73575962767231));
#485=CARTESIAN_POINT('',(12.,-6.41841714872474,-9.0688842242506));
#486=CARTESIAN_POINT('',(12.,-6.12164363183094,-9.54560920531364));
#487=CARTESIAN_POINT('',(12.,-6.0166607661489,-9.70068126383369));
#488=CARTESIAN_POINT('',(12.,-5.79403053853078,-10.0014964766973));
#489=CARTESIAN_POINT('',(12.,-5.67638648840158,-10.1472420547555));
#490=CARTESIAN_POINT('',(12.,-5.45487933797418,-10.3972730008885));
#491=CARTESIAN_POINT('',(12.,-5.35347698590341,-10.5037435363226));
#492=CARTESIAN_POINT('',(12.,-5.14279674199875,-10.7085711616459));
#493=CARTESIAN_POINT('',(12.,-5.03352073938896,-10.8069301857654));
#494=CARTESIAN_POINT('',(12.,-4.80726648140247,-10.9944208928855));
#495=CARTESIAN_POINT('',(12.,-4.69028689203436,-11.0835509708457));
#496=CARTESIAN_POINT('',(12.,-4.44910125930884,-11.2513406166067));
#497=CARTESIAN_POINT('',(12.,-4.32489854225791,-11.330004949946));
#498=CARTESIAN_POINT('',(12.,-4.06863035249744,-11.4764239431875));
#499=CARTESIAN_POINT('',(12.,-3.93650144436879,-11.5440679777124));
#500=CARTESIAN_POINT('',(12.,-3.66642088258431,-11.6663517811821));
#501=CARTESIAN_POINT('',(12.,-3.528472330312,-11.7209983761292));
#502=CARTESIAN_POINT('',(12.,-3.24787660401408,-11.8162983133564));
#503=CARTESIAN_POINT('',(12.,-3.10523150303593,-11.8569577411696));
#504=CARTESIAN_POINT('',(12.,-2.81654054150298,-11.9234999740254));
#505=CARTESIAN_POINT('',(12.,-2.67049527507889,-11.9493853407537));
#506=CARTESIAN_POINT('',(12.,-2.39771004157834,-11.9832224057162));
#507=CARTESIAN_POINT('',(12.,-2.27122026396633,-11.9932206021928));
#508=CARTESIAN_POINT('',(12.,-2.01785681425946,-12.0018542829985));
#509=CARTESIAN_POINT('',(12.,-1.89098317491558,-12.0004907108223));
#510=CARTESIAN_POINT('',(12.,-1.63790716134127,-11.9864242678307));
#511=CARTESIAN_POINT('',(12.,-1.5117045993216,-11.9737247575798));
#512=CARTESIAN_POINT('',(12.,-1.26092539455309,-11.937191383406));
#513=CARTESIAN_POINT('',(12.,-1.13634874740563,-11.9133575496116));
#514=CARTESIAN_POINT('',(12.,-0.89649373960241,-11.8565133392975));
#515=CARTESIAN_POINT('',(12.,-0.781079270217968,-11.824075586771));
#516=CARTESIAN_POINT('',(12.,-0.553227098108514,-11.7500001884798));
#517=CARTESIAN_POINT('',(12.,-0.440790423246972,-11.7083594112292));
#518=CARTESIAN_POINT('',(12.,-0.109014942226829,-11.5704002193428));
#519=CARTESIAN_POINT('',(12.,0.105008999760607,-11.4609917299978));
#520=CARTESIAN_POINT('',(12.,0.529245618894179,-11.2033409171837));
#521=CARTESIAN_POINT('',(12.,0.7380936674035,-11.052882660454));
#522=CARTESIAN_POINT('',(12.,1.13235520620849,-10.7237991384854));
#523=CARTESIAN_POINT('',(12.,1.31775055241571,-10.5451523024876));
#524=CARTESIAN_POINT('',(12.,1.62254806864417,-10.2114249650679));
#525=CARTESIAN_POINT('',(12.,1.74710972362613,-10.0609788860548));
#526=CARTESIAN_POINT('',(12.,1.98246993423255,-9.74964225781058));
#527=CARTESIAN_POINT('',(12.,2.09326266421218,-9.58874733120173));
#528=CARTESIAN_POINT('',(12.,2.40581905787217,-9.09328545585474));
#529=CARTESIAN_POINT('',(12.,2.587676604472,-8.74603704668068));
#530=CARTESIAN_POINT('',(12.,2.87397479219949,-8.10008122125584));
#531=CARTESIAN_POINT('',(12.,2.98657270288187,-7.80482413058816));
#532=CARTESIAN_POINT('',(12.,3.18549424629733,-7.20541001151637));
#533=CARTESIAN_POINT('',(12.,3.27179863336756,-6.90124664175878));
#534=CARTESIAN_POINT('',(12.,3.42251739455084,-6.2865233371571));
#535=CARTESIAN_POINT('',(12.,3.4868517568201,-5.97594429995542));
#536=CARTESIAN_POINT('',(12.,3.59736694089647,-5.35174201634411));
#537=CARTESIAN_POINT('',(12.,3.64355298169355,-5.03811967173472));
#538=CARTESIAN_POINT('',(12.,3.72167895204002,-4.40870301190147));
#539=CARTESIAN_POINT('',(12.,3.75359817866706,-4.0929062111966));
#540=CARTESIAN_POINT('',(12.,3.80648245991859,-3.46037371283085));
#541=CARTESIAN_POINT('',(12.,3.82744548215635,-3.14363785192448));
#542=CARTESIAN_POINT('',(12.,3.86122922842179,-2.50948037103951));
#543=CARTESIAN_POINT('',(12.,3.87404293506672,-2.19205839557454));
#544=CARTESIAN_POINT('',(12.,3.8936152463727,-1.55706059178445));
#545=CARTESIAN_POINT('',(12.,3.90037426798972,-1.23948477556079));
#546=CARTESIAN_POINT('',(12.,3.90914967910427,-0.604217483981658));
#547=CARTESIAN_POINT('',(12.,3.91116525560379,-0.28652599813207));
#548=CARTESIAN_POINT('',(12.,3.91087781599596,0.348865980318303));
#549=CARTESIAN_POINT('',(12.,3.90857465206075,0.666566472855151));
#550=CARTESIAN_POINT('',(12.,3.89916663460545,1.30170933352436));
#551=CARTESIAN_POINT('',(12.,3.89206468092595,1.61915174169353));
#552=CARTESIAN_POINT('',(12.,3.87169775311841,2.25382875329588));
#553=CARTESIAN_POINT('',(12.,3.85843318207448,2.57106336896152));
#554=CARTESIAN_POINT('',(12.,3.82272034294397,3.22079545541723));
#555=CARTESIAN_POINT('',(12.,3.7998499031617,3.55327096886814));
#556=CARTESIAN_POINT('',(12.,3.74162902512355,4.21723380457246));
#557=CARTESIAN_POINT('',(12.,3.70627642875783,4.54872094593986));
#558=CARTESIAN_POINT('',(12.,3.61917575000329,5.20892535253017));
#559=CARTESIAN_POINT('',(12.,3.56746069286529,5.53764683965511));
#560=CARTESIAN_POINT('',(12.,3.44311973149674,6.19111428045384));
#561=CARTESIAN_POINT('',(12.,3.37050185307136,6.51586171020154));
#562=CARTESIAN_POINT('',(12.,3.22557307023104,7.06051440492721));
#563=CARTESIAN_POINT('',(12.,3.15992893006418,7.28217605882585));
#564=CARTESIAN_POINT('',(12.,3.01453978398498,7.7208166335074));
#565=CARTESIAN_POINT('',(12.,2.93479256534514,7.93779481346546));
#566=CARTESIAN_POINT('',(12.,2.67195366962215,8.57887096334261));
#567=CARTESIAN_POINT('',(12.,2.46507240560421,8.99388884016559));
#568=CARTESIAN_POINT('',(12.,2.04688649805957,9.66573179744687));
#569=CARTESIAN_POINT('',(12.,1.85384775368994,9.93380229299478));
#570=CARTESIAN_POINT('',(12.,1.53460329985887,10.3104792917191));
#571=CARTESIAN_POINT('',(12.,1.42326494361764,10.4317793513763));
#572=CARTESIAN_POINT('',(12.,1.19066148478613,10.6644942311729));
#573=CARTESIAN_POINT('',(12.,1.06939830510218,10.7759109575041));
#574=CARTESIAN_POINT('',(12.,0.839451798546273,10.9686160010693));
#575=CARTESIAN_POINT('',(12.,0.732315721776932,11.0517541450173));
#576=CARTESIAN_POINT('',(12.,0.511809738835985,11.2092927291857));
#577=CARTESIAN_POINT('',(12.,0.398441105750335,11.2836949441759));
#578=CARTESIAN_POINT('',(12.,0.165895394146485,11.4228563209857));
#579=CARTESIAN_POINT('',(12.,0.0467174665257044,11.4876140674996));
#580=CARTESIAN_POINT('',(12.,-0.196754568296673,11.6065554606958));
#581=CARTESIAN_POINT('',(12.,-0.32104646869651,11.6607436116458));
#582=CARTESIAN_POINT('',(12.,-0.574834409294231,11.7580847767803));
#583=CARTESIAN_POINT('',(12.,-0.704359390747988,11.801162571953));
#584=CARTESIAN_POINT('',(12.,-0.966798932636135,11.8750880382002));
#585=CARTESIAN_POINT('',(12.,-1.09971189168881,11.9059413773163));
#586=CARTESIAN_POINT('',(12.,-1.36785149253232,11.9549089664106));
#587=CARTESIAN_POINT('',(12.,-1.50307782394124,11.9730249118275));
#588=CARTESIAN_POINT('',(12.,-1.77463986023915,11.9961963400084));
#589=CARTESIAN_POINT('',(12.,-1.91097545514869,12.0012531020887));
#590=CARTESIAN_POINT('',(12.,-2.16915561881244,11.9983805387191));
#591=CARTESIAN_POINT('',(12.,-2.29101669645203,11.9917606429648));
#592=CARTESIAN_POINT('',(12.,-2.53376216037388,11.9680903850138));
#593=CARTESIAN_POINT('',(12.,-2.65464622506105,11.9510367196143));
#594=CARTESIAN_POINT('',(12.,-2.89446289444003,11.9067519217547));
#595=CARTESIAN_POINT('',(12.,-3.01339651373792,11.8795262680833));
#596=CARTESIAN_POINT('',(12.,-3.24862414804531,11.8152635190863));
#597=CARTESIAN_POINT('',(12.,-3.36491714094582,11.7782226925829));
#598=CARTESIAN_POINT('',(12.,-3.59350120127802,11.6950405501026));
#599=CARTESIAN_POINT('',(12.,-3.70581019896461,11.648948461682));
#600=CARTESIAN_POINT('',(12.,-3.92648872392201,11.548108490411));
#601=CARTESIAN_POINT('',(12.,-4.03485685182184,11.4933575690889));
#602=CARTESIAN_POINT('',(12.,-4.35322873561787,11.3170486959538));
#603=CARTESIAN_POINT('',(12.,-4.55664292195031,11.1833816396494));
#604=CARTESIAN_POINT('',(12.,-4.96409580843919,10.8730496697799));
#605=CARTESIAN_POINT('',(12.,-5.16573208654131,10.6932693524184));
#606=CARTESIAN_POINT('',(12.,-5.54232978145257,10.3077301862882));
#607=CARTESIAN_POINT('',(12.,-5.71727899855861,10.1019595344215));
#608=CARTESIAN_POINT('',(12.,-6.01035552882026,9.71139282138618));
#609=CARTESIAN_POINT('',(12.,-6.13298316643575,9.52991865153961));
#610=CARTESIAN_POINT('',(12.,-6.36172605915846,9.15676042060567));
#611=CARTESIAN_POINT('',(12.,-6.46783253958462,8.96507100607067));
#612=CARTESIAN_POINT('',(12.,-6.66475191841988,8.57354683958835));
#613=CARTESIAN_POINT('',(12.,-6.75553226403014,8.37369584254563));
#614=CARTESIAN_POINT('',(12.,-6.92281860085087,7.96820435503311));
#615=CARTESIAN_POINT('',(12.,-6.99932627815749,7.7625645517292));
#616=CARTESIAN_POINT('',(12.,-7.22643844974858,7.08929142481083));
#617=CARTESIAN_POINT('',(12.,-7.35132807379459,6.61288508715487));
#618=CARTESIAN_POINT('',(12.,-7.5022671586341,5.89102752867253));
#619=CARTESIAN_POINT('',(12.,-7.54654262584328,5.64893254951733));
#620=CARTESIAN_POINT('',(12.,-7.6248221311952,5.16305335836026));
#621=CARTESIAN_POINT('',(12.,-7.65882656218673,4.91926921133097));
#622=CARTESIAN_POINT('',(12.,-7.71841574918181,4.42984301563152));
#623=CARTESIAN_POINT('',(12.,-7.74397047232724,4.18419744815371));
#624=CARTESIAN_POINT('',(12.,-7.78810771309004,3.69228759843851));
#625=CARTESIAN_POINT('',(12.,-7.80669015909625,3.44602330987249));
#626=CARTESIAN_POINT('',(12.,-7.83827221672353,2.95332835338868));
#627=CARTESIAN_POINT('',(12.,-7.8512758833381,2.70689793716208));
#628=CARTESIAN_POINT('',(12.,-7.87288468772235,2.21385458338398));
#629=CARTESIAN_POINT('',(12.,-7.88148991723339,1.96724164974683));
#630=CARTESIAN_POINT('',(12.,-7.89232149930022,1.57711739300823));
#631=CARTESIAN_POINT('',(12.,-7.89571038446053,1.43363634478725));
#632=CARTESIAN_POINT('',(12.,-7.90142448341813,1.14665252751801));
#633=CARTESIAN_POINT('',(12.,-7.90374969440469,1.00314975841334));
#634=CARTESIAN_POINT('',(12.,-7.90742828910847,0.716374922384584));
#635=CARTESIAN_POINT('',(12.,-7.90878331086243,0.573102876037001));
#636=CARTESIAN_POINT('',(12.,-7.9105830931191,0.28655396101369));
#637=CARTESIAN_POINT('',(12.,-7.91102785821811,0.143277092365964));
#638=CARTESIAN_POINT('',(12.,-7.9110285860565,0.));
#639=B_SPLINE_CURVE_WITH_KNOTS('',3,(#459,#460,#461,#462,#463,#464,#465,#466,#467,#468,#469,
#470,#471,#472,#473,#474,#475,#476,#477,#478,#479,#480,#481,#482,#483,#484,#485,#486,#487,#488,
#489,#490,#491,#492,#493,#494,#495,#496,#497,#498,#499,#500,#501,#502,#503,#504,#505,#506,#507,
#508,#509,#510,#511,#512,#513,#514,#515,#516,#517,#518,#519,#520,#521,#522,#523,#524,#525,#526,
#527,#528,#529,#530,#531,#532,#533,#534,#535,#536,#537,#538,#539,#540,#541,#542,#543,#544,#545,
#546,#547,#548,#549,#550,#551,#552,#553,#554,#555,#556,#557,#558,#559,#560,#561,#562,#563,#564,
#565,#566,#567,#568,#569,#570,#571,#572,#573,#574,#575,#576,#577,#578,#579,#580,#581,#582,#583,
#584,#585,#586,#587,#588,#589,#590,#591,#592,#593,#594,#595,#596,#597,#598,#599,#600,#601,#602,
#603,#604,#605,#606,#607,#608,#609,#610,#611,#612,#613,#614,#615,#616,#617,#618,#619,#620,#621,
#622,#623,#624,#625,#626,#627,#628,#629,#630,#631,#632,#633,#634,#635,#636,#637,#638),
.UNSPECIFIED.,.T.,.F.,(4,2,2,2,2,2,2,2,2,2,2,2,2,2,2,2,2,2,2,2,2,2,2,2,2,2,2,2,2,2,2,2,2,2,2,2,
2,2,2,2,2,2,2,2,2,2,2,2,2,2,2,2,2,2,2,2,2,2,2,2,2,2,2,2,2,2,2,2,2,2,2,2,2,2,2,2,2,2,2,2,2,2,2,2,
2,2,2,2,2,4),(0.,0.657039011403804,1.31408309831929,1.971270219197,2.62844990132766,
3.28626276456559,3.94406903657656,4.60162535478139,5.25916349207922,6.07836208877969,
6.8976747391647,7.71536835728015,8.53295617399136,9.65565324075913,10.2169292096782,
10.7780587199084,11.2187658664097,11.6593676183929,12.1000458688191,12.5405227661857,
12.9851800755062,13.4296033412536,13.8738330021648,14.3179856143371,14.6981459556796,
15.0782747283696,15.4582908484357,15.8383059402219,16.1975550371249,16.5569265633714,
17.274999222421,18.0443719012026,18.8143362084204,19.3995055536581,19.9849216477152,
21.1561315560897,22.1028947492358,23.0503492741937,24.0012183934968,24.9518138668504,
25.9037843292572,26.8559313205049,27.8088971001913,28.7617972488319,29.7148607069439,
30.6679567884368,31.6204774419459,32.5729358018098,33.5725505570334,34.572338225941,
35.5701207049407,36.5675205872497,37.2605975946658,37.9537834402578,39.3377688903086,
40.3250476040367,40.8184978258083,41.3118526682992,41.7182942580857,42.124653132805,
42.5310715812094,42.9373164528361,43.3462434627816,43.7549806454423,44.1636634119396,
44.5723061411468,44.937985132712,45.303779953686,45.6693780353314,46.0351152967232,
46.3989159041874,46.7628444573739,47.4902491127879,48.2978297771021,49.1057785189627,
49.7619424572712,50.418453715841,51.0763423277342,51.7341531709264,53.2074032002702,
53.9456389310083,54.6838464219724,55.4246502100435,56.1654616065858,56.9057336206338,
57.6459901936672,58.0765500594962,58.5071110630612,58.9369433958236,59.3667735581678),.UNSPECIFIED.);
#640=EDGE_CURVE('E60',#454,#246,#639,.T.);
#641=ORIENTED_EDGE('',*,*,#640,.T.);
#642=ORIENTED_EDGE('',*,*,#249,.T.);
#643=DIRECTION('',(0.,0.,-1.));
#644=VECTOR('',#643,1.);
#645=CARTESIAN_POINT('',(12.,0.,-12.));
#646=LINE('',#645,#644);
#647=EDGE_CURVE('E181',#456,#248,#646,.T.);
#648=ORIENTED_EDGE('',*,*,#647,.F.);
#649=EDGE_LOOP('',(#458,#641,#642,#648));
#650=FACE_BOUND('',#649,.T.);
#651=ADVANCED_FACE('F94',(#650),#448,.T.);
#652=CARTESIAN_POINT('',(-12.,-8.,12.));
#653=DIRECTION('',(0.,0.,1.));
#654=DIRECTION('',(1.,0.,0.));
#655=AXIS2_PLACEMENT_3D('',#652,#653,#654);
#656=PLANE('',#655);
#657=ORIENTED_EDGE('',*,*,#225,.F.);
#658=CARTESIAN_POINT('',(0.,-7.9110285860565,12.));
#659=CARTESIAN_POINT('',(0.219013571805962,-7.91102969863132,12.));
#660=CARTESIAN_POINT('',(0.438027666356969,-7.90999326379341,12.));
#661=CARTESIAN_POINT('',(0.876036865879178,-7.90574714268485,12.));
#662=CARTESIAN_POINT('',(1.09503197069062,-7.90253743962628,12.));
#663=CARTESIAN_POINT('',(1.53302104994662,-7.8936366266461,12.));
#664=CARTESIAN_POINT('',(1.75201501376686,-7.88794497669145,12.));
#665=CARTESIAN_POINT('',(2.18990531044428,-7.87358073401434,12.));
#666=CARTESIAN_POINT('',(2.40880164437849,-7.8649081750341,12.));
#667=CARTESIAN_POINT('',(2.84663378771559,-7.84389210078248,12.));
#668=CARTESIAN_POINT('',(3.06556943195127,-7.83154505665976,12.));
#669=CARTESIAN_POINT('',(3.50314333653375,-7.80233781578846,12.));
#670=CARTESIAN_POINT('',(3.72178159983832,-7.78547766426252,12.));
#671=CARTESIAN_POINT('',(4.15849107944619,-7.74626053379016,12.));
#672=CARTESIAN_POINT('',(4.37656247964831,-7.72390564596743,12.));
#673=CARTESIAN_POINT('',(4.81192697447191,-7.67257977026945,12.));
#674=CARTESIAN_POINT('',(5.0292200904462,-7.64360896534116,12.));
#675=CARTESIAN_POINT('',(5.51592981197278,-7.56973816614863,12.));
#676=CARTESIAN_POINT('',(5.78502690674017,-7.52267302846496,12.));
#677=CARTESIAN_POINT('',(6.32030821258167,-7.41380940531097,12.));
#678=CARTESIAN_POINT('',(6.58649201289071,-7.35200886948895,12.));
#679=CARTESIAN_POINT('',(7.11376722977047,-7.21108699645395,12.));
#680=CARTESIAN_POINT('',(7.37486766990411,-7.13200012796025,12.));
#681=CARTESIAN_POINT('',(7.89008904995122,-6.95374614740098,12.));
#682=CARTESIAN_POINT('',(8.14421088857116,-6.85458163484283,12.));
#683=CARTESIAN_POINT('',(8.73575962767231,-6.59200086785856,12.));
#684=CARTESIAN_POINT('',(9.0688842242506,-6.41841714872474,12.));
#685=CARTESIAN_POINT('',(9.54560920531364,-6.12164363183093,12.));
#686=CARTESIAN_POINT('',(9.70068126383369,-6.01666076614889,12.));
#687=CARTESIAN_POINT('',(10.0014964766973,-5.79403053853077,12.));
#688=CARTESIAN_POINT('',(10.1472420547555,-5.67638648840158,12.));
#689=CARTESIAN_POINT('',(10.3972730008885,-5.45487933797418,12.));
#690=CARTESIAN_POINT('',(10.5037435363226,-5.3534769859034,12.));
#691=CARTESIAN_POINT('',(10.7085711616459,-5.14279674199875,12.));
#692=CARTESIAN_POINT('',(10.8069301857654,-5.03352073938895,12.));
#693=CARTESIAN_POINT('',(10.9944208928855,-4.80726648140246,12.));
#694=CARTESIAN_POINT('',(11.0835509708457,-4.69028689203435,12.));
#695=CARTESIAN_POINT('',(11.2513406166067,-4.44910125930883,12.));
#696=CARTESIAN_POINT('',(11.330004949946,-4.3248985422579,12.));
#697=CARTESIAN_POINT('',(11.4764239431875,-4.06863035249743,12.));
#698=CARTESIAN_POINT('',(11.5440679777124,-3.93650144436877,12.));
#699=CARTESIAN_POINT('',(11.6663517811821,-3.66642088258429,12.));
#700=CARTESIAN_POINT('',(11.7209983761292,-3.52847233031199,12.));
#701=CARTESIAN_POINT('',(11.8162983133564,-3.24787660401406,12.));
#702=CARTESIAN_POINT('',(11.8569577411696,-3.10523150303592,12.));
#703=CARTESIAN_POINT('',(11.9234999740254,-2.81654054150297,12.));
#704=CARTESIAN_POINT('',(11.9493853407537,-2.67049527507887,12.));
#705=CARTESIAN_POINT('',(11.9832224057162,-2.39771004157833,12.));
#706=CARTESIAN_POINT('',(11.9932206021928,-2.27122026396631,12.));
#707=CARTESIAN_POINT('',(12.0018542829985,-2.01785681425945,12.));
#708=CARTESIAN_POINT('',(12.0004907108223,-1.89098317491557,12.));
#709=CARTESIAN_POINT('',(11.9864242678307,-1.63790716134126,12.));
#710=CARTESIAN_POINT('',(11.9737247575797,-1.51170459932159,12.));
#711=CARTESIAN_POINT('',(11.937191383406,-1.26092539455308,12.));
#712=CARTESIAN_POINT('',(11.9133575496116,-1.13634874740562,12.));
#713=CARTESIAN_POINT('',(11.8565133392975,-0.896493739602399,12.));
#714=CARTESIAN_POINT('',(11.824075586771,-0.781079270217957,12.));
#715=CARTESIAN_POINT('',(11.7500001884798,-0.553227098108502,12.));
#716=CARTESIAN_POINT('',(11.7083594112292,-0.440790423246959,12.));
#717=CARTESIAN_POINT('',(11.5704002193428,-0.109014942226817,12.));
#718=CARTESIAN_POINT('',(11.4609917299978,0.105008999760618,12.));
#719=CARTESIAN_POINT('',(11.2033409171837,0.52924561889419,12.));
#720=CARTESIAN_POINT('',(11.052882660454,0.738093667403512,12.));
#721=CARTESIAN_POINT('',(10.7237991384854,1.1323552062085,12.));
#722=CARTESIAN_POINT('',(10.5451523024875,1.31775055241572,12.));
#723=CARTESIAN_POINT('',(10.2114249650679,1.62254806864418,12.));
#724=CARTESIAN_POINT('',(10.0609788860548,1.74710972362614,12.));
#725=CARTESIAN_POINT('',(9.74964225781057,1.98246993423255,12.));
#726=CARTESIAN_POINT('',(9.58874733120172,2.09326266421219,12.));
#727=CARTESIAN_POINT('',(9.09328545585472,2.40581905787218,12.));
#728=CARTESIAN_POINT('',(8.74603704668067,2.58767660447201,12.));
#729=CARTESIAN_POINT('',(8.10008122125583,2.8739747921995,12.));
#730=CARTESIAN_POINT('',(7.80482413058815,2.98657270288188,12.));
#731=CARTESIAN_POINT('',(7.20541001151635,3.18549424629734,12.));
#732=CARTESIAN_POINT('',(6.90124664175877,3.27179863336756,12.));
#733=CARTESIAN_POINT('',(6.28652333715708,3.42251739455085,12.));
#734=CARTESIAN_POINT('',(5.9759442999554,3.48685175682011,12.));
#735=CARTESIAN_POINT('',(5.35174201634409,3.59736694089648,12.));
#736=CARTESIAN_POINT('',(5.0381196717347,3.64355298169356,12.));
#737=CARTESIAN_POINT('',(4.40870301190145,3.72167895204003,12.));
#738=CARTESIAN_POINT('',(4.09290621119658,3.75359817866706,12.));
#739=CARTESIAN_POINT('',(3.46037371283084,3.8064824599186,12.));
#740=CARTESIAN_POINT('',(3.14363785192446,3.82744548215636,12.));
#741=CARTESIAN_POINT('',(2.50948037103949,3.86122922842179,12.));
#742=CARTESIAN_POINT('',(2.19205839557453,3.87404293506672,12.));
#743=CARTESIAN_POINT('',(1.55706059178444,3.89361524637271,12.));
#744=CARTESIAN_POINT('',(1.23948477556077,3.90037426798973,12.));
#745=CARTESIAN_POINT('',(0.604217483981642,3.90914967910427,12.));
#746=CARTESIAN_POINT('',(0.286525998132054,3.91116525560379,12.));
#747=CARTESIAN_POINT('',(-0.348865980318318,3.91087781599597,12.));
#748=CARTESIAN_POINT('',(-0.666566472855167,3.90857465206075,12.));
#749=CARTESIAN_POINT('',(-1.30170933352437,3.89916663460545,12.));
#750=CARTESIAN_POINT('',(-1.61915174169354,3.89206468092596,12.));
#751=CARTESIAN_POINT('',(-2.25382875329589,3.87169775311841,12.));
#752=CARTESIAN_POINT('',(-2.57106336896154,3.85843318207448,12.));
#753=CARTESIAN_POINT('',(-3.22079545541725,3.82272034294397,12.));
#754=CARTESIAN_POINT('',(-3.55327096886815,3.7998499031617,12.));
#755=CARTESIAN_POINT('',(-4.21723380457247,3.74162902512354,12.));
#756=CARTESIAN_POINT('',(-4.54872094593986,3.70627642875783,12.));
#757=CARTESIAN_POINT('',(-5.20892535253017,3.61917575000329,12.));
#758=CARTESIAN_POINT('',(-5.53764683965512,3.56746069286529,12.));
#759=CARTESIAN_POINT('',(-6.19111428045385,3.44311973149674,12.));
#760=CARTESIAN_POINT('',(-6.51586171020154,3.37050185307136,12.));
#761=CARTESIAN_POINT('',(-7.06051440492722,3.22557307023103,12.));
#762=CARTESIAN_POINT('',(-7.28217605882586,3.15992893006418,12.));
#763=CARTESIAN_POINT('',(-7.7208166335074,3.01453978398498,12.));
#764=CARTESIAN_POINT('',(-7.93779481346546,2.93479256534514,12.));
#765=CARTESIAN_POINT('',(-8.57887096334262,2.67195366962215,12.));
#766=CARTESIAN_POINT('',(-8.99388884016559,2.4650724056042,12.));
#767=CARTESIAN_POINT('',(-9.66573179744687,2.04688649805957,12.));
#768=CARTESIAN_POINT('',(-9.93380229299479,1.85384775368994,12.));
#769=CARTESIAN_POINT('',(-10.3104792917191,1.53460329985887,12.));
#770=CARTESIAN_POINT('',(-10.4317793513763,1.42326494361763,12.));
#771=CARTESIAN_POINT('',(-10.6644942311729,1.19066148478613,12.));
#772=CARTESIAN_POINT('',(-10.7759109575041,1.06939830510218,12.));
#773=CARTESIAN_POINT('',(-10.9686160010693,0.839451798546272,12.));
#774=CARTESIAN_POINT('',(-11.0517541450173,0.732315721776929,12.));
#775=CARTESIAN_POINT('',(-11.2092927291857,0.511809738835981,12.));
#776=CARTESIAN_POINT('',(-11.2836949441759,0.39844110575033,12.));
#777=CARTESIAN_POINT('',(-11.4228563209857,0.16589539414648,12.));
#778=CARTESIAN_POINT('',(-11.4876140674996,0.0467174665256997,12.));
#779=CARTESIAN_POINT('',(-11.6065554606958,-0.196754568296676,12.));
#780=CARTESIAN_POINT('',(-11.6607436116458,-0.321046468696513,12.));
#781=CARTESIAN_POINT('',(-11.7580847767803,-0.574834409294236,12.));
#782=CARTESIAN_POINT('',(-11.801162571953,-0.704359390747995,12.));
#783=CARTESIAN_POINT('',(-11.8750880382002,-0.966798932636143,12.));
#784=CARTESIAN_POINT('',(-11.9059413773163,-1.09971189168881,12.));
#785=CARTESIAN_POINT('',(-11.9549089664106,-1.36785149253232,12.));
#786=CARTESIAN_POINT('',(-11.9730249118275,-1.50307782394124,12.));
#787=CARTESIAN_POINT('',(-11.9961963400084,-1.77463986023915,12.));
#788=CARTESIAN_POINT('',(-12.0012531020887,-1.91097545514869,12.));
#789=CARTESIAN_POINT('',(-11.9983805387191,-2.16915561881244,12.));
#790=CARTESIAN_POINT('',(-11.9917606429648,-2.29101669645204,12.));
#791=CARTESIAN_POINT('',(-11.9680903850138,-2.53376216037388,12.));
#792=CARTESIAN_POINT('',(-11.9510367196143,-2.65464622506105,12.));
#793=CARTESIAN_POINT('',(-11.9067519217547,-2.89446289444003,12.));
#794=CARTESIAN_POINT('',(-11.8795262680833,-3.01339651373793,12.));
#795=CARTESIAN_POINT('',(-11.8152635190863,-3.24862414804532,12.));
#796=CARTESIAN_POINT('',(-11.7782226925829,-3.36491714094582,12.));
#797=CARTESIAN_POINT('',(-11.6950405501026,-3.59350120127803,12.));
#798=CARTESIAN_POINT('',(-11.648948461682,-3.70581019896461,12.));
#799=CARTESIAN_POINT('',(-11.548108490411,-3.926488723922,12.));
#800=CARTESIAN_POINT('',(-11.4933575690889,-4.03485685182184,12.));
#801=CARTESIAN_POINT('',(-11.3170486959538,-4.35322873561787,12.));
#802=CARTESIAN_POINT('',(-11.1833816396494,-4.55664292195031,12.));
#803=CARTESIAN_POINT('',(-10.8730496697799,-4.96409580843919,12.));
#804=CARTESIAN_POINT('',(-10.6932693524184,-5.16573208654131,12.));
#805=CARTESIAN_POINT('',(-10.3077301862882,-5.54232978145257,12.));
#806=CARTESIAN_POINT('',(-10.1019595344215,-5.71727899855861,12.));
#807=CARTESIAN_POINT('',(-9.71139282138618,-6.01035552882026,12.));
#808=CARTESIAN_POINT('',(-9.52991865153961,-6.13298316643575,12.));
#809=CARTESIAN_POINT('',(-9.15676042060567,-6.36172605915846,12.));
#810=CARTESIAN_POINT('',(-8.96507100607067,-6.46783253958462,12.));
#811=CARTESIAN_POINT('',(-8.57354683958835,-6.66475191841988,12.));
#812=CARTESIAN_POINT('',(-8.37369584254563,-6.75553226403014,12.));
#813=CARTESIAN_POINT('',(-7.9682043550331,-6.92281860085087,12.));
#814=CARTESIAN_POINT('',(-7.7625645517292,-6.99932627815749,12.));
#815=CARTESIAN_POINT('',(-7.08929142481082,-7.22643844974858,12.));
#816=CARTESIAN_POINT('',(-6.61288508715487,-7.35132807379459,12.));
#817=CARTESIAN_POINT('',(-5.89102752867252,-7.5022671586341,12.));
#818=CARTESIAN_POINT('',(-5.64893254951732,-7.54654262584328,12.));
#819=CARTESIAN_POINT('',(-5.16305335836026,-7.6248221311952,12.));
#820=CARTESIAN_POINT('',(-4.91926921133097,-7.65882656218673,12.));
#821=CARTESIAN_POINT('',(-4.42984301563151,-7.71841574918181,12.));
#822=CARTESIAN_POINT('',(-4.1841974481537,-7.74397047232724,12.));
#823=CARTESIAN_POINT('',(-3.6922875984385,-7.78810771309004,12.));
#824=CARTESIAN_POINT('',(-3.44602330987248,-7.80669015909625,12.));
#825=CARTESIAN_POINT('',(-2.95332835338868,-7.83827221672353,12.));
#826=CARTESIAN_POINT('',(-2.70689793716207,-7.85127588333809,12.));
#827=CARTESIAN_POINT('',(-2.21385458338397,-7.87288468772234,12.));
#828=CARTESIAN_POINT('',(-1.96724164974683,-7.88148991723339,12.));
#829=CARTESIAN_POINT('',(-1.57711739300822,-7.89232149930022,12.));
#830=CARTESIAN_POINT('',(-1.43363634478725,-7.89571038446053,12.));
#831=CARTESIAN_POINT('',(-1.14665252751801,-7.90142448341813,12.));
#832=CARTESIAN_POINT('',(-1.00314975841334,-7.90374969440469,12.));
#833=CARTESIAN_POINT('',(-0.716374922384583,-7.90742828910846,12.));
#834=CARTESIAN_POINT('',(-0.573102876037,-7.90878331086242,12.));
#835=CARTESIAN_POINT('',(-0.286553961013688,-7.9105830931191,12.));
#836=CARTESIAN_POINT('',(-0.143277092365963,-7.91102785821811,12.));
#837=CARTESIAN_POINT('',(0.,-7.9110285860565,12.));
#838=B_SPLINE_CURVE_WITH_KNOTS('',3,(#658,#659,#660,#661,#662,#663,#664,#665,#666,#667,#668,
#669,#670,#671,#672,#673,#674,#675,#676,#677,#678,#679,#680,#681,#682,#683,#684,#685,#686,#687,
#688,#689,#690,#691,#692,#693,#694,#695,#696,#697,#698,#699,#700,#701,#702,#703,#704,#705,#706,
#707,#708,#709,#710,#711,#712,#713,#714,#715,#716,#717,#718,#719,#720,#721,#722,#723,#724,#725,
#726,#727,#728,#729,#730,#731,#732,#733,#734,#735,#736,#737,#738,#739,#740,#741,#742,#743,#744,
#745,#746,#747,#748,#749,#750,#751,#752,#753,#754,#755,#756,#757,#758,#759,#760,#761,#762,#763,
#764,#765,#766,#767,#768,#769,#770,#771,#772,#773,#774,#775,#776,#777,#778,#779,#780,#781,#782,
#783,#784,#785,#786,#787,#788,#789,#790,#791,#792,#793,#794,#795,#796,#797,#798,#799,#800,#801,
#802,#803,#804,#805,#806,#807,#808,#809,#810,#811,#812,#813,#814,#815,#816,#817,#818,#819,#820,
#821,#822,#823,#824,#825,#826,#827,#828,#829,#830,#831,#832,#833,#834,#835,#836,#837),
.UNSPECIFIED.,.T.,.F.,(4,2,2,2,2,2,2,2,2,2,2,2,2,2,2,2,2,2,2,2,2,2,2,2,2,2,2,2,2,2,2,2,2,2,2,2,
2,2,2,2,2,2,2,2,2,2,2,2,2,2,2,2,2,2,2,2,2,2,2,2,2,2,2,2,2,2,2,2,2,2,2,2,2,2,2,2,2,2,2,2,2,2,2,2,
2,2,2,2,2,4),(0.,0.657039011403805,1.31408309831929,1.971270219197,2.62844990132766,
3.28626276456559,3.94406903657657,4.60162535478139,5.25916349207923,6.07836208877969,
6.8976747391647,7.71536835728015,8.53295617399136,9.65565324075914,10.2169292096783,
10.7780587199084,11.2187658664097,11.6593676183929,12.1000458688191,12.5405227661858,
12.9851800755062,13.4296033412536,13.8738330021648,14.3179856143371,14.6981459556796,
15.0782747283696,15.4582908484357,15.8383059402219,16.1975550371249,16.5569265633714,
17.274999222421,18.0443719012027,18.8143362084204,19.3995055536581,19.9849216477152,
21.1561315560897,22.1028947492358,23.0503492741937,24.0012183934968,24.9518138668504,
25.9037843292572,26.8559313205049,27.8088971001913,28.7617972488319,29.7148607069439,
30.6679567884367,31.6204774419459,32.5729358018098,33.5725505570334,34.572338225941,
35.5701207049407,36.5675205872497,37.2605975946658,37.9537834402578,39.3377688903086,
40.3250476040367,40.8184978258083,41.3118526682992,41.7182942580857,42.124653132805,
42.5310715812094,42.9373164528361,43.3462434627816,43.7549806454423,44.1636634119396,
44.5723061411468,44.937985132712,45.303779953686,45.6693780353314,46.0351152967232,
46.3989159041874,46.7628444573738,47.4902491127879,48.297829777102,49.1057785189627,
49.7619424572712,50.418453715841,51.0763423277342,51.7341531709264,53.2074032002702,
53.9456389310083,54.6838464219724,55.4246502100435,56.1654616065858,56.9057336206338,
57.6459901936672,58.0765500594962,58.5071110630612,58.9369433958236,59.3667735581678),.UNSPECIFIED.);
#839=EDGE_CURVE('E99',#216,#454,#838,.T.);
#840=ORIENTED_EDGE('',*,*,#839,.T.);
#841=ORIENTED_EDGE('',*,*,#457,.T.);
#842=DIRECTION('',(1.,0.,0.));
#843=VECTOR('',#842,1.);
#844=CARTESIAN_POINT('',(-12.,0.,12.));
#845=LINE('',#844,#843);
#846=EDGE_CURVE('E180',#224,#456,#845,.T.);
#847=ORIENTED_EDGE('',*,*,#846,.F.);
#848=EDGE_LOOP('',(#657,#840,#841,#847));
#849=FACE_BOUND('',#848,.T.);
#850=ADVANCED_FACE('F138',(#849),#656,.T.);
#851=CARTESIAN_POINT('',(0.,96.,0.));
#852=DIRECTION('',(0.,-1.,0.));
#853=DIRECTION('',(0.,0.,-1.));
#854=AXIS2_PLACEMENT_3D('',#851,#852,#853);
#855=CYLINDRICAL_SURFACE('',#854,6.);
#856=CARTESIAN_POINT('',(0.,96.,0.));
#857=DIRECTION('',(0.,1.,0.));
#858=DIRECTION('',(0.,0.,1.));
#859=AXIS2_PLACEMENT_3D('',#856,#857,#858);
#860=CIRCLE('',#859,6.);
#861=CARTESIAN_POINT('',(0.,96.,6.));
#862=VERTEX_POINT('',#861);
#863=EDGE_CURVE('E13',#862,#862,#860,.T.);
#864=ORIENTED_EDGE('',*,*,#863,.F.);
#865=EDGE_LOOP('',(#864));
#866=FACE_BOUND('',#865,.T.);
#867=CARTESIAN_POINT('',(0.,0.,0.));
#868=DIRECTION('',(0.,1.,0.));
#869=DIRECTION('',(0.,0.,1.));
#870=AXIS2_PLACEMENT_3D('',#867,#868,#869);
#871=CIRCLE('',#870,6.);
#872=CARTESIAN_POINT('',(0.,0.,6.));
#873=VERTEX_POINT('',#872);
#874=EDGE_CURVE('E53',#873,#873,#871,.T.);
#875=ORIENTED_EDGE('',*,*,#874,.T.);
#876=EDGE_LOOP('',(#875));
#877=FACE_BOUND('',#876,.T.);
#878=ADVANCED_FACE('F46',(#866,#877),#855,.T.);
#879=CARTESIAN_POINT('',(0.,96.,0.));
#880=DIRECTION('',(0.,1.,0.));
#881=DIRECTION('',(0.,0.,1.));
#882=AXIS2_PLACEMENT_3D('',#879,#880,#881);
#883=PLANE('',#882);
#884=ORIENTED_EDGE('',*,*,#863,.T.);
#885=EDGE_LOOP('',(#884));
#886=FACE_BOUND('',#885,.T.);
#887=ADVANCED_FACE('F117',(#886),#883,.T.);
#888=CARTESIAN_POINT('',(-12.,0.,12.));
#889=DIRECTION('',(0.,1.,0.));
#890=DIRECTION('',(0.,0.,1.));
#891=AXIS2_PLACEMENT_3D('',#888,#889,#890);
#892=PLANE('',#891);
#893=ORIENTED_EDGE('',*,*,#231,.T.);
#894=ORIENTED_EDGE('',*,*,#846,.T.);
#895=ORIENTED_EDGE('',*,*,#647,.T.);
#896=ORIENTED_EDGE('',*,*,#439,.T.);
#897=EDGE_LOOP('',(#893,#894,#895,#896));
#898=FACE_BOUND('',#897,.T.);
#899=ORIENTED_EDGE('',*,*,#874,.F.);
#900=EDGE_LOOP('',(#899));
#901=FACE_BOUND('',#900,.T.);
#902=ADVANCED_FACE('F115',(#898,#901),#892,.T.);
#903=CARTESIAN_POINT('',(0.,-2.,0.));
#904=DIRECTION('',(0.,1.,0.));
#905=DIRECTION('',(0.,0.,1.));
#906=AXIS2_PLACEMENT_3D('',#903,#904,#905);
#907=TOROIDAL_SURFACE('',#906,10.9705627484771,6.);
#908=ORIENTED_EDGE('',*,*,#432,.F.);
#909=ORIENTED_EDGE('',*,*,#640,.F.);
#910=ORIENTED_EDGE('',*,*,#839,.F.);
#911=ORIENTED_EDGE('',*,*,#217,.F.);
#912=EDGE_LOOP('',(#908,#909,#910,#911));
#913=FACE_BOUND('',#912,.T.);
#914=CARTESIAN_POINT('',(0.,-7.96284793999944,0.));
#915=DIRECTION('',(0.,1.,0.));
#916=DIRECTION('',(0.,0.,1.));
#917=AXIS2_PLACEMENT_3D('',#914,#915,#916);
#918=CIRCLE('',#917,10.3038960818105);
#919=CARTESIAN_POINT('',(0.,-7.96284793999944,10.3038960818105));
#920=VERTEX_POINT('',#919);
#921=EDGE_CURVE('E173',#920,#920,#918,.T.);
#922=ORIENTED_EDGE('',*,*,#921,.T.);
#923=EDGE_LOOP('',(#922));
#924=FACE_BOUND('',#923,.T.);
#925=ADVANCED_FACE('F86',(#913,#924),#907,.T.);
#926=CARTESIAN_POINT('',(0.,0.,0.));
#927=DIRECTION('',(0.,1.,0.));
#928=DIRECTION('',(0.,0.,1.));
#929=AXIS2_PLACEMENT_3D('',#926,#927,#928);
#930=CYLINDRICAL_SURFACE('',#929,10.3038960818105);
#931=ORIENTED_EDGE('',*,*,#921,.F.);
#932=EDGE_LOOP('',(#931));
#933=FACE_BOUND('',#932,.T.);
#934=CARTESIAN_POINT('',(0.,-8.,0.));
#935=DIRECTION('',(0.,1.,0.));
#936=DIRECTION('',(0.,0.,1.));
#937=AXIS2_PLACEMENT_3D('',#934,#935,#936);
#938=CIRCLE('',#937,10.3038960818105);
#939=CARTESIAN_POINT('',(0.,-8.,10.3038960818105));
#940=VERTEX_POINT('',#939);
#941=EDGE_CURVE('E48',#940,#940,#938,.T.);
#942=ORIENTED_EDGE('',*,*,#941,.T.);
#943=EDGE_LOOP('',(#942));
#944=FACE_BOUND('',#943,.T.);
#945=ADVANCED_FACE('F124',(#933,#944),#930,.T.);
#946=CARTESIAN_POINT('',(-12.,-8.,12.));
#947=DIRECTION('',(0.,1.,0.));
#948=DIRECTION('',(0.,0.,1.));
#949=AXIS2_PLACEMENT_3D('',#946,#947,#948);
#950=PLANE('',#949);
#951=ORIENTED_EDGE('',*,*,#941,.F.);
#952=EDGE_LOOP('',(#951));
#953=FACE_BOUND('',#952,.T.);
#954=ADVANCED_FACE('F163',(#953),#950,.F.);
#955=CLOSED_SHELL('',(#235,#443,#651,#850,#878,#887,#902,#925,#945,#954));
#956=MANIFOLD_SOLID_BREP('B2',#955);
#957=ADVANCED_BREP_SHAPE_REPRESENTATION('',(#18,#956),#14);
#958=SHAPE_DEFINITION_REPRESENTATION(#9,#957);
ENDSEC;
END-ISO-10303-21;
